# cml_to_cmos : LEF d'integration de MSPHY5973 (prompt-063-leo, 29/09/2026). PIN du LEF source cml_to_cmos.lef,
# OBS recalculees depuis le metal reel du GDS (Metal1 a Metal5, vias compris), moins les PIN de la meme couche.
VERSION 5.7 ;
  NOWIREEXTENSIONATPIN ON ;
  DIVIDERCHAR "/" ;
  BUSBITCHARS "[]" ;
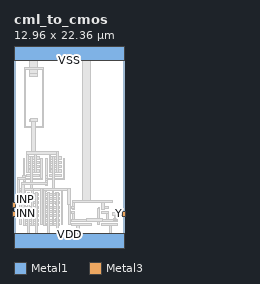
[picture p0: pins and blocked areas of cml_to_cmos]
MACRO cml_to_cmos
  CLASS BLOCK ;
  FOREIGN cml_to_cmos ;
  ORIGIN 0.000 0.000 ;
  SIZE 12.960 BY 22.360 ;
  PIN VDD
    DIRECTION INOUT ;
    USE POWER ;
    PORT
      LAYER Metal1 ;
        RECT 0.000 -1.000 12.960 1.000 ;
    END
  END VDD
  PIN VSS
    DIRECTION INOUT ;
    USE GROUND ;
    PORT
      LAYER Metal1 ;
        RECT 0.000 21.360 12.960 23.360 ;
    END
  END VSS
  PIN INN
    DIRECTION INPUT ;
    USE SIGNAL ;
    ANTENNAGATEAREA 0.832000 ;
    PORT
      LAYER Metal3 ;
        RECT -0.150 3.000 0.150 3.600 ;
    END
  END INN
  PIN INP
    DIRECTION INPUT ;
    USE SIGNAL ;
    ANTENNAGATEAREA 0.832000 ;
    PORT
      LAYER Metal3 ;
        RECT -0.150 4.100 0.150 4.700 ;
    END
  END INP
  PIN Y
    DIRECTION OUTPUT ;
    USE SIGNAL ;
    ANTENNADIFFAREA 1.020000 ;
    PORT
      LAYER Metal3 ;
        RECT 12.810 3.000 13.110 3.600 ;
    END
  END Y
  OBS
    LAYER Metal1 ;
      RECT 7.350 1.000 7.650 1.930 ;
      RECT 6.790 1.930 9.150 2.190 ;
      RECT 10.280 1.930 12.140 2.190 ;
      RECT 11.190 1.000 11.490 1.930 ;
      RECT 1.390 1.930 2.930 2.190 ;
      RECT 1.070 1.900 1.390 2.220 ;
      RECT 3.830 1.930 5.370 2.190 ;
      RECT 3.510 1.900 3.830 2.220 ;
      RECT 1.070 2.440 2.480 2.700 ;
      RECT 2.800 2.440 2.930 2.700 ;
      RECT 2.480 2.410 2.800 2.730 ;
      RECT 3.510 2.440 4.920 2.700 ;
      RECT 5.240 2.440 5.370 2.700 ;
      RECT 4.920 2.410 5.240 2.730 ;
      RECT 1.390 2.950 2.930 3.210 ;
      RECT 1.070 2.920 1.390 3.240 ;
      RECT 3.830 2.950 5.370 3.210 ;
      RECT 3.510 2.920 3.830 3.240 ;
      RECT 6.790 2.440 8.500 2.700 ;
      RECT 8.820 2.440 9.150 2.700 ;
      RECT 8.500 2.410 8.820 2.730 ;
      RECT 6.790 3.375 7.150 3.635 ;
      RECT 6.850 2.700 7.110 3.375 ;
      RECT 10.280 2.440 11.720 2.700 ;
      RECT 12.040 2.440 12.140 2.700 ;
      RECT 11.720 2.410 12.040 2.730 ;
      RECT 10.280 3.375 11.140 3.635 ;
      RECT 10.860 2.700 11.120 3.375 ;
      RECT 1.070 3.460 2.480 3.720 ;
      RECT 2.800 3.460 2.930 3.720 ;
      RECT 2.480 3.430 2.800 3.750 ;
      RECT 3.510 3.460 4.920 3.720 ;
      RECT 5.240 3.460 5.370 3.720 ;
      RECT 4.920 3.430 5.240 3.750 ;
      RECT 9.910 3.970 10.070 4.015 ;
      RECT 9.880 2.060 10.100 3.970 ;
      RECT 1.390 3.970 2.930 4.230 ;
      RECT 1.070 3.940 1.390 4.260 ;
      RECT 3.830 3.970 5.370 4.230 ;
      RECT 3.510 3.940 3.830 4.260 ;
      RECT 1.070 4.480 2.480 4.740 ;
      RECT 2.800 4.480 2.930 4.740 ;
      RECT 2.480 4.450 2.800 4.770 ;
      RECT 3.510 4.480 4.920 4.740 ;
      RECT 5.240 4.480 5.370 4.740 ;
      RECT 4.920 4.450 5.240 4.770 ;
      RECT 6.390 2.060 6.610 4.960 ;
      RECT 1.390 4.990 2.930 5.250 ;
      RECT 1.070 4.960 1.390 5.280 ;
      RECT 3.830 4.990 5.370 5.250 ;
      RECT 3.510 4.960 3.830 5.280 ;
      RECT 1.070 5.500 2.480 5.760 ;
      RECT 2.800 5.500 2.930 5.760 ;
      RECT 2.480 5.470 2.800 5.790 ;
      RECT 3.510 5.500 4.920 5.760 ;
      RECT 5.240 5.500 5.370 5.760 ;
      RECT 4.920 5.470 5.240 5.790 ;
      RECT 5.580 2.060 5.740 6.140 ;
      RECT 0.700 2.060 0.860 5.980 ;
      RECT 0.700 5.980 1.390 6.010 ;
      RECT 0.700 6.010 3.140 6.270 ;
      RECT 3.140 2.060 3.300 6.270 ;
      RECT 1.070 6.270 1.390 6.300 ;
      RECT 3.830 6.010 5.370 6.270 ;
      RECT 3.510 5.980 3.830 6.300 ;
      RECT 2.150 7.710 2.950 7.970 ;
      RECT 1.490 7.680 2.150 8.000 ;
      RECT 4.780 7.710 5.580 7.970 ;
      RECT 4.120 7.680 4.780 8.000 ;
      RECT 2.150 8.220 2.950 8.480 ;
      RECT 1.490 8.190 2.150 8.510 ;
      RECT 4.780 8.220 5.580 8.480 ;
      RECT 4.120 8.190 4.780 8.510 ;
      RECT 2.150 8.730 2.950 8.990 ;
      RECT 1.490 8.700 2.150 9.020 ;
      RECT 4.780 8.730 5.580 8.990 ;
      RECT 4.120 8.700 4.780 9.020 ;
      RECT 2.150 9.240 2.950 9.500 ;
      RECT 1.490 9.210 2.150 9.530 ;
      RECT 4.780 9.240 5.580 9.500 ;
      RECT 4.120 9.210 4.780 9.530 ;
      RECT 1.120 7.860 1.280 9.880 ;
      RECT 1.090 7.500 1.310 7.860 ;
      RECT 1.090 7.130 1.310 7.500 ;
      RECT 3.160 7.500 3.320 9.880 ;
      RECT 1.310 7.300 3.320 7.500 ;
      RECT 3.750 7.860 3.910 9.880 ;
      RECT 3.720 7.500 3.940 7.860 ;
      RECT 5.790 7.300 5.950 9.880 ;
      RECT 3.720 6.670 3.940 7.500 ;
      RECT 3.940 7.300 5.790 7.500 ;
      RECT 2.150 9.750 2.950 10.010 ;
      RECT 1.490 9.720 2.150 10.040 ;
      RECT 4.780 9.750 5.580 10.010 ;
      RECT 4.120 9.720 4.780 10.040 ;
      RECT 1.840 14.150 2.800 14.465 ;
      RECT 1.180 13.650 1.340 20.330 ;
      RECT 1.870 19.830 2.770 20.330 ;
      RECT 1.840 19.515 2.800 19.830 ;
      RECT 1.870 19.460 2.770 19.515 ;
      RECT 1.870 20.490 2.770 21.360 ;
      RECT 1.180 20.330 3.460 20.490 ;
      RECT 3.300 13.650 3.460 20.330 ;
      RECT 1.180 13.490 3.460 13.650 ;
      RECT 6.850 4.145 7.110 4.640 ;
      RECT 6.790 3.885 7.150 4.145 ;
      RECT 6.850 3.880 7.110 3.885 ;
      RECT 6.850 4.640 11.640 4.940 ;
      RECT 10.600 3.885 11.140 4.145 ;
      RECT 10.280 3.885 10.340 4.145 ;
      RECT 10.340 3.880 10.600 4.640 ;
      RECT 8.100 4.940 8.980 21.360 ;
    LAYER Via1 ;
      RECT 1.565 0.005 1.755 0.195 ;
      RECT 2.545 0.005 2.735 0.195 ;
      RECT 4.005 0.005 4.195 0.195 ;
      RECT 4.985 0.005 5.175 0.195 ;
      RECT 1.565 0.450 1.755 0.640 ;
      RECT 2.545 0.450 2.735 0.640 ;
      RECT 4.005 0.450 4.195 0.640 ;
      RECT 4.985 0.450 5.175 0.640 ;
      RECT 1.095 1.965 1.285 2.155 ;
      RECT 2.055 1.965 2.245 2.155 ;
      RECT 3.535 1.965 3.725 2.155 ;
      RECT 4.495 1.965 4.685 2.155 ;
      RECT 1.565 2.475 1.755 2.665 ;
      RECT 2.545 2.475 2.735 2.665 ;
      RECT 4.005 2.475 4.195 2.665 ;
      RECT 4.985 2.475 5.175 2.665 ;
      RECT 8.565 2.475 8.755 2.665 ;
      RECT 9.895 2.475 10.085 2.665 ;
      RECT 11.785 2.475 11.975 2.665 ;
      RECT 1.095 2.985 1.285 3.175 ;
      RECT 2.055 2.985 2.245 3.175 ;
      RECT 3.535 2.985 3.725 3.175 ;
      RECT 4.495 2.985 4.685 3.175 ;
      RECT 1.565 3.495 1.755 3.685 ;
      RECT 2.545 3.495 2.735 3.685 ;
      RECT 4.005 3.495 4.195 3.685 ;
      RECT 4.985 3.495 5.175 3.685 ;
      RECT 1.095 4.005 1.285 4.195 ;
      RECT 2.055 4.005 2.245 4.195 ;
      RECT 3.535 4.005 3.725 4.195 ;
      RECT 4.495 4.005 4.685 4.195 ;
      RECT 1.565 4.515 1.755 4.705 ;
      RECT 2.545 4.515 2.735 4.705 ;
      RECT 4.005 4.515 4.195 4.705 ;
      RECT 4.985 4.515 5.175 4.705 ;
      RECT 6.405 4.545 6.595 4.735 ;
      RECT 1.095 5.025 1.285 5.215 ;
      RECT 2.055 5.025 2.245 5.215 ;
      RECT 3.535 5.025 3.725 5.215 ;
      RECT 4.495 5.025 4.685 5.215 ;
      RECT 1.565 5.535 1.755 5.725 ;
      RECT 2.545 5.535 2.735 5.725 ;
      RECT 4.005 5.535 4.195 5.725 ;
      RECT 4.985 5.535 5.175 5.725 ;
      RECT 1.095 6.045 1.285 6.235 ;
      RECT 2.055 6.045 2.245 6.235 ;
      RECT 3.535 6.045 3.725 6.235 ;
      RECT 4.495 6.045 4.685 6.235 ;
      RECT 3.735 6.805 3.925 6.995 ;
      RECT 1.105 7.375 1.295 7.565 ;
      RECT 1.945 7.745 2.135 7.935 ;
      RECT 4.575 7.745 4.765 7.935 ;
      RECT 1.505 8.255 1.695 8.445 ;
      RECT 2.385 8.255 2.575 8.445 ;
      RECT 4.135 8.255 4.325 8.445 ;
      RECT 5.015 8.255 5.205 8.445 ;
      RECT 1.945 8.765 2.135 8.955 ;
      RECT 4.575 8.765 4.765 8.955 ;
      RECT 1.505 9.275 1.695 9.465 ;
      RECT 2.385 9.275 2.575 9.465 ;
      RECT 4.135 9.275 4.325 9.465 ;
      RECT 5.015 9.275 5.205 9.465 ;
      RECT 1.945 9.785 2.135 9.975 ;
      RECT 4.575 9.785 4.765 9.975 ;
      RECT 2.020 14.225 2.210 14.415 ;
      RECT 2.430 14.225 2.620 14.415 ;
    LAYER Metal2 ;
      RECT 8.550 2.420 10.450 2.720 ;
      RECT 11.770 2.420 11.990 3.500 ;
      RECT 1.550 -0.050 1.770 5.790 ;
      RECT 2.530 -0.050 2.750 5.790 ;
      RECT 3.990 -0.050 4.210 5.790 ;
      RECT 4.970 -0.050 5.190 5.790 ;
      RECT 3.670 6.750 3.980 7.250 ;
      RECT 1.040 7.320 1.350 7.820 ;
      RECT 1.080 1.900 1.300 6.040 ;
      RECT 1.930 6.300 2.150 10.060 ;
      RECT 1.080 6.040 2.260 6.300 ;
      RECT 2.040 1.900 2.260 6.040 ;
      RECT 3.520 1.900 3.740 6.090 ;
      RECT 4.480 1.900 4.700 6.090 ;
      RECT 3.520 6.090 6.350 6.350 ;
      RECT 6.350 4.450 6.650 6.350 ;
      RECT 4.560 6.350 4.780 10.060 ;
      RECT 1.490 8.170 1.710 10.290 ;
      RECT 2.370 8.170 2.590 10.290 ;
      RECT 4.120 8.170 4.340 10.290 ;
      RECT 2.080 10.620 2.500 14.135 ;
      RECT 1.890 14.135 2.750 14.505 ;
      RECT 1.490 10.290 5.000 10.620 ;
      RECT 5.000 8.170 5.220 10.620 ;
    LAYER Via2 ;
      RECT 11.785 3.205 11.975 3.395 ;
      RECT 3.735 6.805 3.925 6.995 ;
      RECT 1.105 7.375 1.295 7.565 ;
    LAYER Metal3 ;
      RECT 11.620 3.150 12.810 3.450 ;
      RECT 0.900 3.600 1.180 6.750 ;
      RECT 0.150 3.300 1.180 3.600 ;
      RECT 0.900 6.750 3.980 7.050 ;
      RECT 0.360 4.700 0.640 7.320 ;
      RECT 0.150 4.400 0.640 4.700 ;
      RECT 0.360 7.320 1.350 7.620 ;
  END
END cml_to_cmos
END LIBRARY

